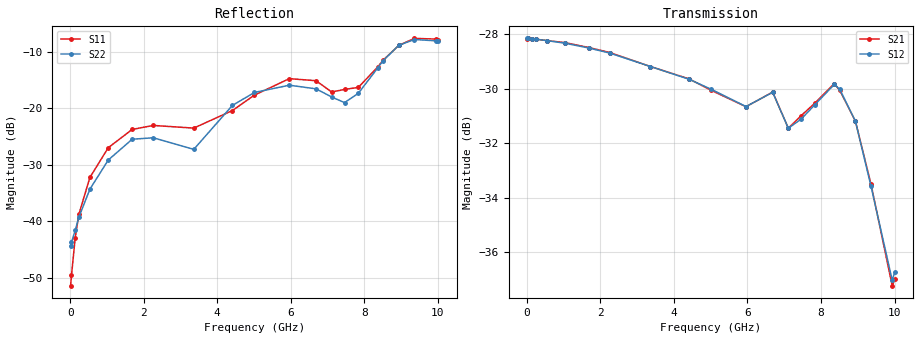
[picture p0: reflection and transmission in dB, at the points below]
! Device ID: PE43704
! Dir: z:\PE43704\PE43704_Char_1_20130516\PE43704\AMB\3p400V\27p25dB
! Serial: 14
! Insertion: A
! Impedance: 50 ohm
! Temp: Amb
! VDD: 3.400V
! Attenuation Step: 27.25dB
! IDD: 1.140804e-01mA
#  Hz  S  RI  R  50
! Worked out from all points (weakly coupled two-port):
!   401 points, 10 MHz to 10.01 GHz, reference 50 ohm
!   highest |S21| = -28.16 dB at 35 MHz (marker M1); lowest = -37.2 dB at 9.935 GHz (marker M2)
!   lowest |S11| = -51.3 dB at 10 MHz (marker M3), VSWR 1.01, Z = 50.3 + j0.0485 ohm
!   |S11| at or under -10 dB: start of sweep to 8.723 GHz
!   |S22| runs from -44.3 to -7.8 dB; largest |S21 - S12| = 0.00067
!   S11 on the Smith chart (normalised r, x): 10 MHz: 1.01, +0.00; 7.46 GHz: 0.78, +0.15; 8.51 GHz: 0.81, +0.46; 9.36 GHz: 0.54, +0.49; 10.01 GHz: 0.47, +0.28
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1e7  0.00266 0.000483  0.039 -6.43e-05  0.0391 -7.47e-05  0.0061 0.000445
3.5e7  0.00282 0.00179  0.0391 -0.000394  0.0391 -0.000341  0.00636 0.00149
1.35e8  0.00252 0.00666  0.039 -0.0014  0.039 -0.00135  0.00605 0.00574
2.35e8  0.000864 0.0115  0.0389 -0.00229  0.0389 -0.00232  0.00461 0.00986
5.35e8  -0.00774 0.0232  0.0384 -0.00516  0.0384 -0.00513  -0.00374 0.0189
1.035e9  -0.0332 0.0301  0.0372 -0.00954  0.0371 -0.00954  -0.0277 0.0212
1.685e9  -0.063 0.0161  0.0345 -0.015  0.0345 -0.0148  -0.0532 0.00256
2.26e9  -0.0705 -0.00106  0.0316 -0.0189  0.0315 -0.0189  -0.0534 -0.0126
3.36e9  -0.0668 0.000583  0.0245 -0.0246  0.0245 -0.0246  -0.043 0.00537
4.41e9  -0.0841 0.0451  0.018 -0.0276  0.0179 -0.0276  -0.0924 0.0518
5.01e9  -0.1079 0.0739  0.0146 -0.0278  0.0149 -0.0278  -0.1257 0.0569
5.96e9  -0.1547 0.0972  0.00924 -0.0278  0.0093 -0.0278  -0.1505 0.0542
6.685e9  -0.1543 0.0832  0.00686 -0.0304  0.00673 -0.0304  -0.1388 0.0528
7.11e9  -0.1234 0.0645  0.00171 -0.0267  0.00154 -0.0267  -0.106 0.068
7.46e9  -0.1126 0.0941  0.00244 -0.0281  0.00243 -0.0277  -0.0762 0.0823
7.835e9  -0.0661 0.1379  0.00177 -0.0297  0.00179 -0.0295  -0.0591 0.122
8.36e9  -0.0333 0.2287  -0.00623 -0.0317  -0.00611 -0.0316  -0.0735 0.2143
8.51e9  -0.0362 0.2637  -0.00887 -0.0301  -0.00906 -0.0302  -0.0859 0.2487
8.935e9  -0.0878 0.3485  -0.0139 -0.0238  -0.0139 -0.0238  -0.1522 0.326
9.36e9  -0.1781 0.3747  -0.0125 -0.017  -0.0126 -0.0167  -0.2378 0.3283
9.935e9  -0.3013 0.2766  -0.00386 -0.0132  -0.00432 -0.0134  -0.345 0.1916
1.001e10  -0.3125 0.2503  -0.00301 -0.0138  -0.00292 -0.0143  -0.3535 0.1631
